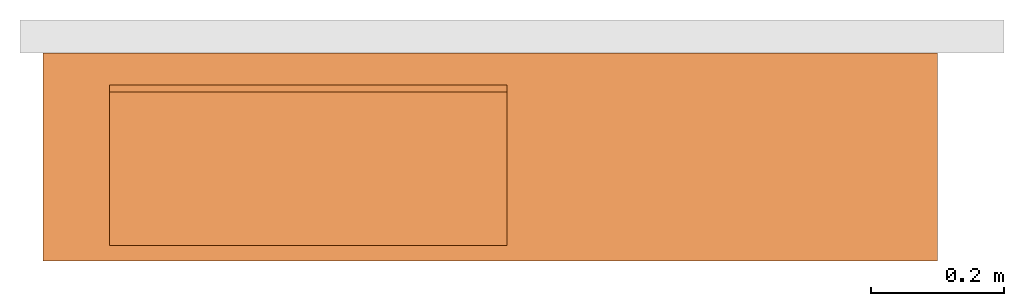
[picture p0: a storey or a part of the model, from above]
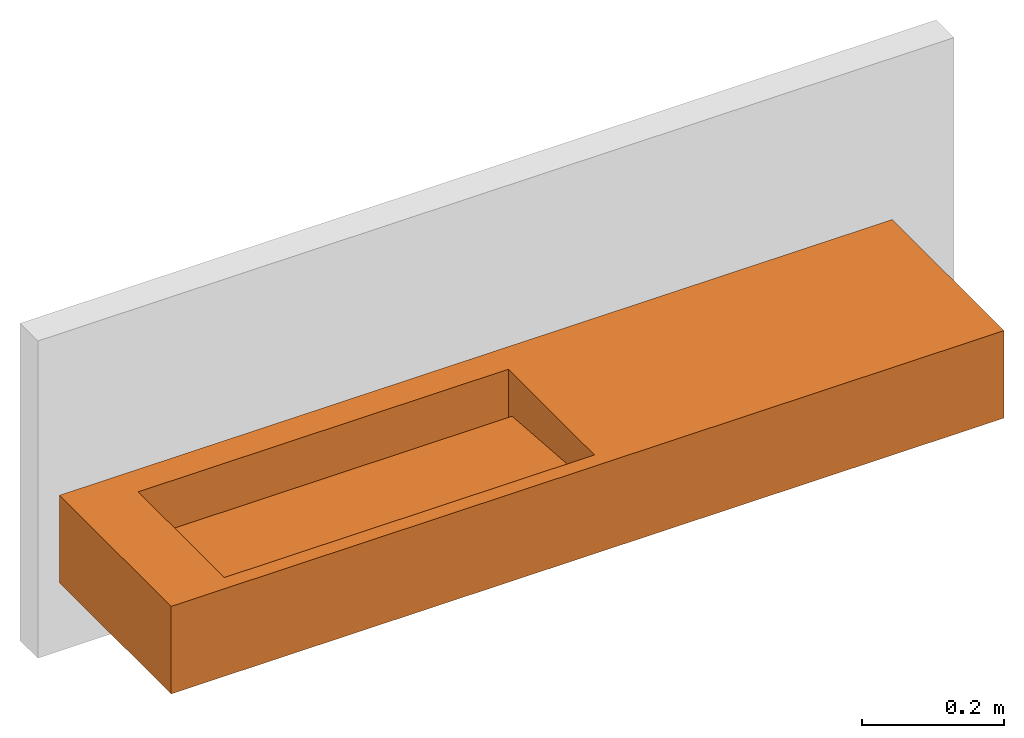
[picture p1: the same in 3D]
Properties of the parts of a building model (IFC2X3)

# File
Description: ViewDefinition [CoordinationView]
Time: 2018-10-01T10:38:25
Written by: The EXPRESS Data Manager Version 5.01.0100.02.64mod : 6 Jun 2012
Made in: 20140709_2115(x64) - Exporter 2014.0.2014.0709 - Default UI
Comment: STEP Physical File produced by: The EXPRESS Data Manager Version 5.01.0100.02.64mod : 6 Jun 2012 * Module: EDMstepFileFactory/EDMstandAlone * Creation date: Mon Oct 01 10:38:25 2018 * Host: BIM-HP * Database: C:\Users\dcole\AppData\Local\Temp\{7F269895-EAE4-4332-BE54-3F2B4D28185C}\ifc * Database version: 5507 * Database creation date: Mon Oct 01 10:38:24 2018 * Schema: IFC2X3 * Model: DataRepository.ifc * Model creation date: Mon Oct 01 10:38:25 2018 * Header model: DataRepository.ifc_HeaderModel * Header model creation date: Mon Oct 01 10:38:25 2018 * EDMuser: sdai-user * EDMgroup: sdai-group * License ID and type: 5605 : Permanent license. Expiry date: * EDMstepFileFactory options: 020000

# IfcProject
LongName: P:\Fastrack\54890_BELL-CHEM New Project\Bespoke Drawings\TROUGHS\LUCID TOP WITH INTEGRATED BASIN.ifc

# IfcSite, Default
RefLatitude: 42, 24, 53, 508911; RefLongitude: -71, -15, -29, -58837; RefElevation: 0 mm

# IfcBuilding
Pset_BuildingCommon - NumberOfStoreys: 1

# IfcBuildingStorey, Level 1
LongName: Level 1; Elevation: 0 mm
Constraints - Elevation Base: Project Base Point; Elevation: 0 mm
Dimensions - Computation Height: 0 mm
Identity Data - Structural: no; Building Story: yes; Name: Level 1
Graphics - Symbol at End 2 Default: yes; Color: 0; Line Weight: 1; Symbol at End 1 Default: no; Line Pattern: -3000010

# IfcBuildingElementProxy: Dolphin ALAVO Lucid Top with Integrated Basin, LUCID TOP WITH INTEGRATED BASIN:Dolphin ALAVO Lucid Top with Integrated Basin:79511
In: Level 1
Material: Drain, Corian
Dimensions - Volume: 0.0520309 m3; Length: Dependent on application dimensions fully customisable; Projection: Dependent on application dimensions fully customisable; Height: Dependent on application dimensions fully customisable
Constraints - Moves With Nearby Elements: no; Host: Level : Level 1; Level: Level: Level 1; Offset: 0 mm
Phasing - Phase Created: New Construction
Pset_ManufacturerTypeInformation - Manufacturer: Dolphin Solutions Limited
Pset_BuildingElementProxyCommon - Reference: Dolphin ALAVO Lucid Top with Integrated Basin
Identity Data - Assembly Code: D2090900; Manufacturer: Dolphin Solutions Limited; Description: Top with integrated basin; Tel No.: +44 (0) 1424 202224; URL: www.dolphinsolutions.co.uk; Fax No.: +44 (0) 1424 205200; Assembly Description: Misc. Other Plumbing Systems; Address: Southpoint, Compass Park, Bodiam, Robertbridge, TN32 5BS; Model: Lucid top with integrated basin; Email: info@dolphinsolutions.co.uk
General - Product Data: Seamless top and integrated basins to enhance cleaning. Individual wastes. Front fascia to hide the trap and waste pipe. Designed to integrate with alavo Supaloo System.; Product Page Link: http://www.dolphinsolutions.co.uk/en/product/lucid-vanity-trough

# IfcWallStandardCase: Basic Wall:Wall 1, Basic Wall:Wall 1:3092
In: Level 1
Type - PredefinedType: STANDARD; Material: Default Wall 50 mm
Type - Analytical Properties - Roughness: 1; Absorptance: 0.1
Type - Construction - Width: 50 mm; Wrapping at Inserts: Do not wrap; Function: Exterior
Type - Graphics - Coarse Scale Fill Color: 8454143
Constraints - Top Extension Distance: 0 mm; Related to Mass: no; Room Bounding: yes; Base Constraint: Level: Level 1; Base Extension Distance: 0 mm; Unconnected Height: 543.637 mm; Location Line: Finish Face: Interior; Top is Attached: no; Base Offset: 2.89275 mm; Base is Attached: no; Top Offset: 0 mm
Structural - Structural Usage: Non-bearing; Structural: no; Enable Analytical Model: no
Phasing - Phase Created: New Construction
Dimensions - Volume: 0.040365 m3; Area: 0.8073 m2; Length: 1485 mm
Pset_WallCommon - Reference: Wall 1; LoadBearing: no; ExtendToStructure: no; IsExternal: yes
